###############################################################
#  Generated by:      Cadence Innovus 23.14-s088_1
#  OS:                Linux x86_64(Host ID mustatikli-be3.tuni.fi)
#  Generated on:      Mon Sep 22 14:50:03 2025
#  Design:            IN22FDX_S1DU_BFUG_W00256B032M04C128
#  Command:           write_lef_abstract -exclude_obs_layers $top_layer -stripe_pins -pg_pin_layers 10 [file join models [get_db flow_report_name] [get_db [current_design] .name].lef]
###############################################################

VERSION 5.8 ;

BUSBITCHARS "[]" ;
DIVIDERCHAR "/" ;

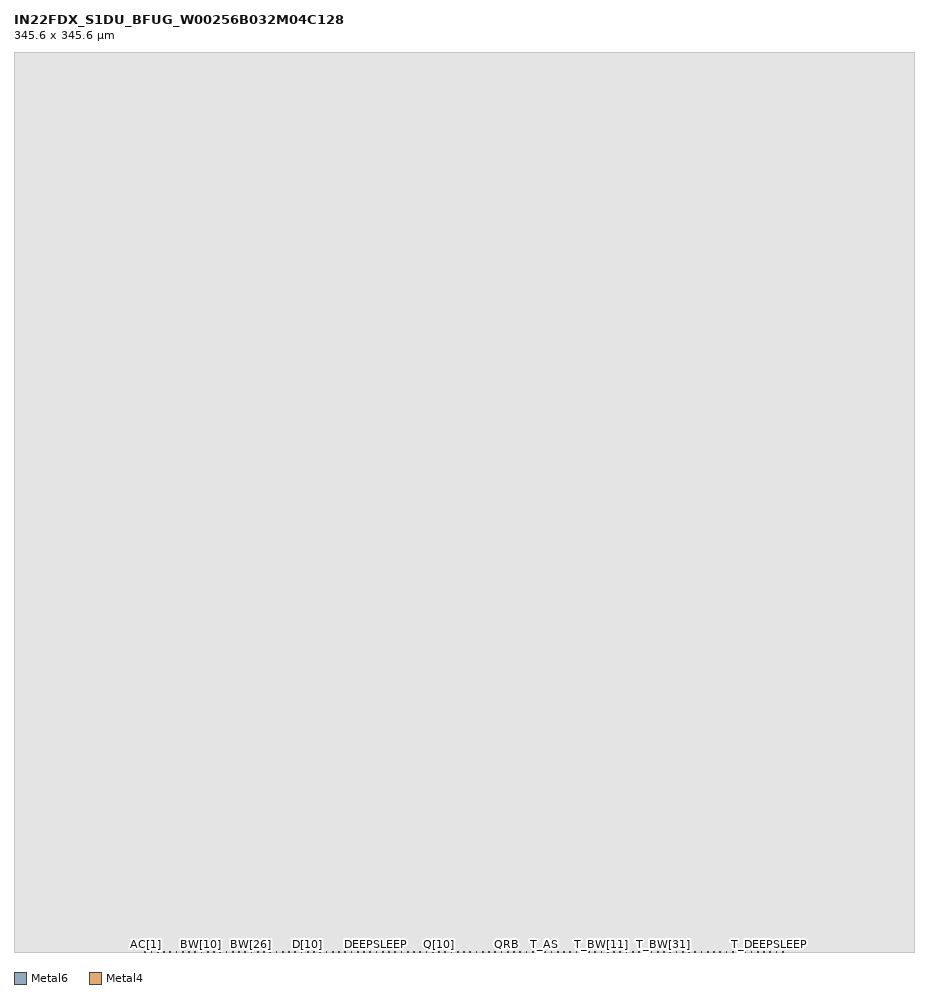
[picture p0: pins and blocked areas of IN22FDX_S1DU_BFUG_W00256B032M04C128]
MACRO IN22FDX_S1DU_BFUG_W00256B032M04C128
  CLASS BLOCK ;
  SIZE 345.600000 BY 345.600000 ;
  FOREIGN IN22FDX_S1DU_BFUG_W00256B032M04C128 0.000000 0.000000 ;
  ORIGIN 0 0 ;
  SYMMETRY X Y R90 ;
  PIN CLK
    DIRECTION INPUT ;
    USE SIGNAL ;
    PORT
      LAYER Metal6 ;
        RECT 98.460000 0.000000 98.540000 0.250000 ;
    END
  END CLK
  PIN CEN
    DIRECTION INPUT ;
    USE SIGNAL ;
    PORT
      LAYER Metal4 ;
        RECT 98.260000 0.000000 98.340000 0.250000 ;
    END
  END CEN
  PIN RDWEN
    DIRECTION INPUT ;
    USE SIGNAL ;
    PORT
      LAYER Metal6 ;
        RECT 199.260000 0.000000 199.340000 0.250000 ;
    END
  END RDWEN
  PIN DEEPSLEEP
    DIRECTION INPUT ;
    USE SIGNAL ;
    PORT
      LAYER Metal4 ;
        RECT 139.060000 0.000000 139.140000 0.250000 ;
    END
  END DEEPSLEEP
  PIN POWERGATE
    DIRECTION INPUT ;
    USE SIGNAL ;
    PORT
      LAYER Metal6 ;
        RECT 148.860000 0.000000 148.940000 0.250000 ;
    END
  END POWERGATE
  PIN AS
    DIRECTION INPUT ;
    USE SIGNAL ;
    PORT
      LAYER Metal4 ;
        RECT 52.660000 0.000000 52.740000 0.250000 ;
    END
  END AS
  PIN AW[4]
    DIRECTION INPUT ;
    USE SIGNAL ;
    PORT
      LAYER Metal6 ;
        RECT 57.660000 0.000000 57.740000 0.250000 ;
    END
  END AW[4]
  PIN AW[3]
    DIRECTION INPUT ;
    USE SIGNAL ;
    PORT
      LAYER Metal4 ;
        RECT 57.460000 0.000000 57.540000 0.250000 ;
    END
  END AW[3]
  PIN AW[2]
    DIRECTION INPUT ;
    USE SIGNAL ;
    PORT
      LAYER Metal6 ;
        RECT 55.260000 0.000000 55.340000 0.250000 ;
    END
  END AW[2]
  PIN AW[1]
    DIRECTION INPUT ;
    USE SIGNAL ;
    PORT
      LAYER Metal4 ;
        RECT 55.060000 0.000000 55.140000 0.250000 ;
    END
  END AW[1]
  PIN AW[0]
    DIRECTION INPUT ;
    USE SIGNAL ;
    PORT
      LAYER Metal6 ;
        RECT 52.860000 0.000000 52.940000 0.250000 ;
    END
  END AW[0]
  PIN AC[1]
    DIRECTION INPUT ;
    USE SIGNAL ;
    PORT
      LAYER Metal6 ;
        RECT 50.460000 0.000000 50.540000 0.250000 ;
    END
  END AC[1]
  PIN AC[0]
    DIRECTION INPUT ;
    USE SIGNAL ;
    PORT
      LAYER Metal4 ;
        RECT 50.260000 0.000000 50.340000 0.250000 ;
    END
  END AC[0]
  PIN D[31]
    DIRECTION INPUT ;
    USE SIGNAL ;
    PORT
      LAYER Metal6 ;
        RECT 136.860000 0.000000 136.940000 0.250000 ;
    END
  END D[31]
  PIN D[30]
    DIRECTION INPUT ;
    USE SIGNAL ;
    PORT
      LAYER Metal4 ;
        RECT 136.660000 0.000000 136.740000 0.250000 ;
    END
  END D[30]
  PIN D[29]
    DIRECTION INPUT ;
    USE SIGNAL ;
    PORT
      LAYER Metal6 ;
        RECT 134.460000 0.000000 134.540000 0.250000 ;
    END
  END D[29]
  PIN D[28]
    DIRECTION INPUT ;
    USE SIGNAL ;
    PORT
      LAYER Metal4 ;
        RECT 134.260000 0.000000 134.340000 0.250000 ;
    END
  END D[28]
  PIN D[27]
    DIRECTION INPUT ;
    USE SIGNAL ;
    PORT
      LAYER Metal6 ;
        RECT 132.060000 0.000000 132.140000 0.250000 ;
    END
  END D[27]
  PIN D[26]
    DIRECTION INPUT ;
    USE SIGNAL ;
    PORT
      LAYER Metal4 ;
        RECT 131.860000 0.000000 131.940000 0.250000 ;
    END
  END D[26]
  PIN D[25]
    DIRECTION INPUT ;
    USE SIGNAL ;
    PORT
      LAYER Metal6 ;
        RECT 129.660000 0.000000 129.740000 0.250000 ;
    END
  END D[25]
  PIN D[24]
    DIRECTION INPUT ;
    USE SIGNAL ;
    PORT
      LAYER Metal4 ;
        RECT 129.460000 0.000000 129.540000 0.250000 ;
    END
  END D[24]
  PIN D[23]
    DIRECTION INPUT ;
    USE SIGNAL ;
    PORT
      LAYER Metal6 ;
        RECT 127.260000 0.000000 127.340000 0.250000 ;
    END
  END D[23]
  PIN D[22]
    DIRECTION INPUT ;
    USE SIGNAL ;
    PORT
      LAYER Metal4 ;
        RECT 127.060000 0.000000 127.140000 0.250000 ;
    END
  END D[22]
  PIN D[21]
    DIRECTION INPUT ;
    USE SIGNAL ;
    PORT
      LAYER Metal6 ;
        RECT 124.860000 0.000000 124.940000 0.250000 ;
    END
  END D[21]
  PIN D[20]
    DIRECTION INPUT ;
    USE SIGNAL ;
    PORT
      LAYER Metal4 ;
        RECT 124.660000 0.000000 124.740000 0.250000 ;
    END
  END D[20]
  PIN D[19]
    DIRECTION INPUT ;
    USE SIGNAL ;
    PORT
      LAYER Metal6 ;
        RECT 122.460000 0.000000 122.540000 0.250000 ;
    END
  END D[19]
  PIN D[18]
    DIRECTION INPUT ;
    USE SIGNAL ;
    PORT
      LAYER Metal4 ;
        RECT 122.260000 0.000000 122.340000 0.250000 ;
    END
  END D[18]
  PIN D[17]
    DIRECTION INPUT ;
    USE SIGNAL ;
    PORT
      LAYER Metal6 ;
        RECT 120.060000 0.000000 120.140000 0.250000 ;
    END
  END D[17]
  PIN D[16]
    DIRECTION INPUT ;
    USE SIGNAL ;
    PORT
      LAYER Metal4 ;
        RECT 119.860000 0.000000 119.940000 0.250000 ;
    END
  END D[16]
  PIN D[15]
    DIRECTION INPUT ;
    USE SIGNAL ;
    PORT
      LAYER Metal6 ;
        RECT 117.660000 0.000000 117.740000 0.250000 ;
    END
  END D[15]
  PIN D[14]
    DIRECTION INPUT ;
    USE SIGNAL ;
    PORT
      LAYER Metal4 ;
        RECT 117.460000 0.000000 117.540000 0.250000 ;
    END
  END D[14]
  PIN D[13]
    DIRECTION INPUT ;
    USE SIGNAL ;
    PORT
      LAYER Metal6 ;
        RECT 115.260000 0.000000 115.340000 0.250000 ;
    END
  END D[13]
  PIN D[12]
    DIRECTION INPUT ;
    USE SIGNAL ;
    PORT
      LAYER Metal4 ;
        RECT 115.060000 0.000000 115.140000 0.250000 ;
    END
  END D[12]
  PIN D[11]
    DIRECTION INPUT ;
    USE SIGNAL ;
    PORT
      LAYER Metal6 ;
        RECT 112.860000 0.000000 112.940000 0.250000 ;
    END
  END D[11]
  PIN D[10]
    DIRECTION INPUT ;
    USE SIGNAL ;
    PORT
      LAYER Metal4 ;
        RECT 112.660000 0.000000 112.740000 0.250000 ;
    END
  END D[10]
  PIN D[9]
    DIRECTION INPUT ;
    USE SIGNAL ;
    PORT
      LAYER Metal6 ;
        RECT 110.460000 0.000000 110.540000 0.250000 ;
    END
  END D[9]
  PIN D[8]
    DIRECTION INPUT ;
    USE SIGNAL ;
    PORT
      LAYER Metal4 ;
        RECT 110.260000 0.000000 110.340000 0.250000 ;
    END
  END D[8]
  PIN D[7]
    DIRECTION INPUT ;
    USE SIGNAL ;
    PORT
      LAYER Metal6 ;
        RECT 108.060000 0.000000 108.140000 0.250000 ;
    END
  END D[7]
  PIN D[6]
    DIRECTION INPUT ;
    USE SIGNAL ;
    PORT
      LAYER Metal4 ;
        RECT 107.860000 0.000000 107.940000 0.250000 ;
    END
  END D[6]
  PIN D[5]
    DIRECTION INPUT ;
    USE SIGNAL ;
    PORT
      LAYER Metal6 ;
        RECT 105.660000 0.000000 105.740000 0.250000 ;
    END
  END D[5]
  PIN D[4]
    DIRECTION INPUT ;
    USE SIGNAL ;
    PORT
      LAYER Metal4 ;
        RECT 105.460000 0.000000 105.540000 0.250000 ;
    END
  END D[4]
  PIN D[3]
    DIRECTION INPUT ;
    USE SIGNAL ;
    PORT
      LAYER Metal6 ;
        RECT 103.260000 0.000000 103.340000 0.250000 ;
    END
  END D[3]
  PIN D[2]
    DIRECTION INPUT ;
    USE SIGNAL ;
    PORT
      LAYER Metal4 ;
        RECT 103.060000 0.000000 103.140000 0.250000 ;
    END
  END D[2]
  PIN D[1]
    DIRECTION INPUT ;
    USE SIGNAL ;
    PORT
      LAYER Metal6 ;
        RECT 100.860000 0.000000 100.940000 0.250000 ;
    END
  END D[1]
  PIN D[0]
    DIRECTION INPUT ;
    USE SIGNAL ;
    PORT
      LAYER Metal4 ;
        RECT 100.660000 0.000000 100.740000 0.250000 ;
    END
  END D[0]
  PIN BW[31]
    DIRECTION INPUT ;
    USE SIGNAL ;
    PORT
      LAYER Metal6 ;
        RECT 96.060000 0.000000 96.140000 0.250000 ;
    END
  END BW[31]
  PIN BW[30]
    DIRECTION INPUT ;
    USE SIGNAL ;
    PORT
      LAYER Metal4 ;
        RECT 95.860000 0.000000 95.940000 0.250000 ;
    END
  END BW[30]
  PIN BW[29]
    DIRECTION INPUT ;
    USE SIGNAL ;
    PORT
      LAYER Metal6 ;
        RECT 93.660000 0.000000 93.740000 0.250000 ;
    END
  END BW[29]
  PIN BW[28]
    DIRECTION INPUT ;
    USE SIGNAL ;
    PORT
      LAYER Metal4 ;
        RECT 93.460000 0.000000 93.540000 0.250000 ;
    END
  END BW[28]
  PIN BW[27]
    DIRECTION INPUT ;
    USE SIGNAL ;
    PORT
      LAYER Metal6 ;
        RECT 91.260000 0.000000 91.340000 0.250000 ;
    END
  END BW[27]
  PIN BW[26]
    DIRECTION INPUT ;
    USE SIGNAL ;
    PORT
      LAYER Metal4 ;
        RECT 91.060000 0.000000 91.140000 0.250000 ;
    END
  END BW[26]
  PIN BW[25]
    DIRECTION INPUT ;
    USE SIGNAL ;
    PORT
      LAYER Metal6 ;
        RECT 88.860000 0.000000 88.940000 0.250000 ;
    END
  END BW[25]
  PIN BW[24]
    DIRECTION INPUT ;
    USE SIGNAL ;
    PORT
      LAYER Metal4 ;
        RECT 88.660000 0.000000 88.740000 0.250000 ;
    END
  END BW[24]
  PIN BW[23]
    DIRECTION INPUT ;
    USE SIGNAL ;
    PORT
      LAYER Metal6 ;
        RECT 86.460000 0.000000 86.540000 0.250000 ;
    END
  END BW[23]
  PIN BW[22]
    DIRECTION INPUT ;
    USE SIGNAL ;
    PORT
      LAYER Metal4 ;
        RECT 86.260000 0.000000 86.340000 0.250000 ;
    END
  END BW[22]
  PIN BW[21]
    DIRECTION INPUT ;
    USE SIGNAL ;
    PORT
      LAYER Metal6 ;
        RECT 84.060000 0.000000 84.140000 0.250000 ;
    END
  END BW[21]
  PIN BW[20]
    DIRECTION INPUT ;
    USE SIGNAL ;
    PORT
      LAYER Metal4 ;
        RECT 83.860000 0.000000 83.940000 0.250000 ;
    END
  END BW[20]
  PIN BW[19]
    DIRECTION INPUT ;
    USE SIGNAL ;
    PORT
      LAYER Metal6 ;
        RECT 81.660000 0.000000 81.740000 0.250000 ;
    END
  END BW[19]
  PIN BW[18]
    DIRECTION INPUT ;
    USE SIGNAL ;
    PORT
      LAYER Metal4 ;
        RECT 81.460000 0.000000 81.540000 0.250000 ;
    END
  END BW[18]
  PIN BW[17]
    DIRECTION INPUT ;
    USE SIGNAL ;
    PORT
      LAYER Metal6 ;
        RECT 79.260000 0.000000 79.340000 0.250000 ;
    END
  END BW[17]
  PIN BW[16]
    DIRECTION INPUT ;
    USE SIGNAL ;
    PORT
      LAYER Metal4 ;
        RECT 79.060000 0.000000 79.140000 0.250000 ;
    END
  END BW[16]
  PIN BW[15]
    DIRECTION INPUT ;
    USE SIGNAL ;
    PORT
      LAYER Metal6 ;
        RECT 76.860000 0.000000 76.940000 0.250000 ;
    END
  END BW[15]
  PIN BW[14]
    DIRECTION INPUT ;
    USE SIGNAL ;
    PORT
      LAYER Metal4 ;
        RECT 76.660000 0.000000 76.740000 0.250000 ;
    END
  END BW[14]
  PIN BW[13]
    DIRECTION INPUT ;
    USE SIGNAL ;
    PORT
      LAYER Metal6 ;
        RECT 74.460000 0.000000 74.540000 0.250000 ;
    END
  END BW[13]
  PIN BW[12]
    DIRECTION INPUT ;
    USE SIGNAL ;
    PORT
      LAYER Metal4 ;
        RECT 74.260000 0.000000 74.340000 0.250000 ;
    END
  END BW[12]
  PIN BW[11]
    DIRECTION INPUT ;
    USE SIGNAL ;
    PORT
      LAYER Metal6 ;
        RECT 72.060000 0.000000 72.140000 0.250000 ;
    END
  END BW[11]
  PIN BW[10]
    DIRECTION INPUT ;
    USE SIGNAL ;
    PORT
      LAYER Metal4 ;
        RECT 71.860000 0.000000 71.940000 0.250000 ;
    END
  END BW[10]
  PIN BW[9]
    DIRECTION INPUT ;
    USE SIGNAL ;
    PORT
      LAYER Metal6 ;
        RECT 69.660000 0.000000 69.740000 0.250000 ;
    END
  END BW[9]
  PIN BW[8]
    DIRECTION INPUT ;
    USE SIGNAL ;
    PORT
      LAYER Metal4 ;
        RECT 69.460000 0.000000 69.540000 0.250000 ;
    END
  END BW[8]
  PIN BW[7]
    DIRECTION INPUT ;
    USE SIGNAL ;
    PORT
      LAYER Metal6 ;
        RECT 67.260000 0.000000 67.340000 0.250000 ;
    END
  END BW[7]
  PIN BW[6]
    DIRECTION INPUT ;
    USE SIGNAL ;
    PORT
      LAYER Metal4 ;
        RECT 67.060000 0.000000 67.140000 0.250000 ;
    END
  END BW[6]
  PIN BW[5]
    DIRECTION INPUT ;
    USE SIGNAL ;
    PORT
      LAYER Metal6 ;
        RECT 64.860000 0.000000 64.940000 0.250000 ;
    END
  END BW[5]
  PIN BW[4]
    DIRECTION INPUT ;
    USE SIGNAL ;
    PORT
      LAYER Metal4 ;
        RECT 64.660000 0.000000 64.740000 0.250000 ;
    END
  END BW[4]
  PIN BW[3]
    DIRECTION INPUT ;
    USE SIGNAL ;
    PORT
      LAYER Metal6 ;
        RECT 62.460000 0.000000 62.540000 0.250000 ;
    END
  END BW[3]
  PIN BW[2]
    DIRECTION INPUT ;
    USE SIGNAL ;
    PORT
      LAYER Metal4 ;
        RECT 62.260000 0.000000 62.340000 0.250000 ;
    END
  END BW[2]
  PIN BW[1]
    DIRECTION INPUT ;
    USE SIGNAL ;
    PORT
      LAYER Metal6 ;
        RECT 60.060000 0.000000 60.140000 0.250000 ;
    END
  END BW[1]
  PIN BW[0]
    DIRECTION INPUT ;
    USE SIGNAL ;
    PORT
      LAYER Metal4 ;
        RECT 59.860000 0.000000 59.940000 0.250000 ;
    END
  END BW[0]
  PIN T_BIST
    DIRECTION INPUT ;
    USE SIGNAL ;
    PORT
      LAYER Metal4 ;
        RECT 211.060000 0.000000 211.140000 0.250000 ;
    END
  END T_BIST
  PIN T_LOGIC
    DIRECTION INPUT ;
    USE SIGNAL ;
    PORT
      LAYER Metal6 ;
        RECT 290.460000 0.000000 290.540000 0.250000 ;
    END
  END T_LOGIC
  PIN T_CEN
    DIRECTION INPUT ;
    USE SIGNAL ;
    PORT
      LAYER Metal6 ;
        RECT 249.660000 0.000000 249.740000 0.250000 ;
    END
  END T_CEN
  PIN T_RDWEN
    DIRECTION INPUT ;
    USE SIGNAL ;
    PORT
      LAYER Metal6 ;
        RECT 292.860000 0.000000 292.940000 0.250000 ;
    END
  END T_RDWEN
  PIN T_DEEPSLEEP
    DIRECTION INPUT ;
    USE SIGNAL ;
    PORT
      LAYER Metal4 ;
        RECT 290.260000 0.000000 290.340000 0.250000 ;
    END
  END T_DEEPSLEEP
  PIN T_POWERGATE
    DIRECTION INPUT ;
    USE SIGNAL ;
    PORT
      LAYER Metal4 ;
        RECT 292.660000 0.000000 292.740000 0.250000 ;
    END
  END T_POWERGATE
  PIN T_AS
    DIRECTION INPUT ;
    USE SIGNAL ;
    PORT
      LAYER Metal4 ;
        RECT 203.860000 0.000000 203.940000 0.250000 ;
    END
  END T_AS
  PIN T_AW[4]
    DIRECTION INPUT ;
    USE SIGNAL ;
    PORT
      LAYER Metal6 ;
        RECT 208.860000 0.000000 208.940000 0.250000 ;
    END
  END T_AW[4]
  PIN T_AW[3]
    DIRECTION INPUT ;
    USE SIGNAL ;
    PORT
      LAYER Metal4 ;
        RECT 208.660000 0.000000 208.740000 0.250000 ;
    END
  END T_AW[3]
  PIN T_AW[2]
    DIRECTION INPUT ;
    USE SIGNAL ;
    PORT
      LAYER Metal6 ;
        RECT 206.460000 0.000000 206.540000 0.250000 ;
    END
  END T_AW[2]
  PIN T_AW[1]
    DIRECTION INPUT ;
    USE SIGNAL ;
    PORT
      LAYER Metal4 ;
        RECT 206.260000 0.000000 206.340000 0.250000 ;
    END
  END T_AW[1]
  PIN T_AW[0]
    DIRECTION INPUT ;
    USE SIGNAL ;
    PORT
      LAYER Metal6 ;
        RECT 204.060000 0.000000 204.140000 0.250000 ;
    END
  END T_AW[0]
  PIN T_AC[1]
    DIRECTION INPUT ;
    USE SIGNAL ;
    PORT
      LAYER Metal6 ;
        RECT 201.660000 0.000000 201.740000 0.250000 ;
    END
  END T_AC[1]
  PIN T_AC[0]
    DIRECTION INPUT ;
    USE SIGNAL ;
    PORT
      LAYER Metal4 ;
        RECT 201.460000 0.000000 201.540000 0.250000 ;
    END
  END T_AC[0]
  PIN T_D[31]
    DIRECTION INPUT ;
    USE SIGNAL ;
    PORT
      LAYER Metal6 ;
        RECT 288.060000 0.000000 288.140000 0.250000 ;
    END
  END T_D[31]
  PIN T_D[30]
    DIRECTION INPUT ;
    USE SIGNAL ;
    PORT
      LAYER Metal4 ;
        RECT 287.860000 0.000000 287.940000 0.250000 ;
    END
  END T_D[30]
  PIN T_D[29]
    DIRECTION INPUT ;
    USE SIGNAL ;
    PORT
      LAYER Metal6 ;
        RECT 285.660000 0.000000 285.740000 0.250000 ;
    END
  END T_D[29]
  PIN T_D[28]
    DIRECTION INPUT ;
    USE SIGNAL ;
    PORT
      LAYER Metal4 ;
        RECT 285.460000 0.000000 285.540000 0.250000 ;
    END
  END T_D[28]
  PIN T_D[27]
    DIRECTION INPUT ;
    USE SIGNAL ;
    PORT
      LAYER Metal6 ;
        RECT 283.260000 0.000000 283.340000 0.250000 ;
    END
  END T_D[27]
  PIN T_D[26]
    DIRECTION INPUT ;
    USE SIGNAL ;
    PORT
      LAYER Metal4 ;
        RECT 283.060000 0.000000 283.140000 0.250000 ;
    END
  END T_D[26]
  PIN T_D[25]
    DIRECTION INPUT ;
    USE SIGNAL ;
    PORT
      LAYER Metal6 ;
        RECT 280.860000 0.000000 280.940000 0.250000 ;
    END
  END T_D[25]
  PIN T_D[24]
    DIRECTION INPUT ;
    USE SIGNAL ;
    PORT
      LAYER Metal4 ;
        RECT 280.660000 0.000000 280.740000 0.250000 ;
    END
  END T_D[24]
  PIN T_D[23]
    DIRECTION INPUT ;
    USE SIGNAL ;
    PORT
      LAYER Metal6 ;
        RECT 278.460000 0.000000 278.540000 0.250000 ;
    END
  END T_D[23]
  PIN T_D[22]
    DIRECTION INPUT ;
    USE SIGNAL ;
    PORT
      LAYER Metal4 ;
        RECT 278.260000 0.000000 278.340000 0.250000 ;
    END
  END T_D[22]
  PIN T_D[21]
    DIRECTION INPUT ;
    USE SIGNAL ;
    PORT
      LAYER Metal6 ;
        RECT 276.060000 0.000000 276.140000 0.250000 ;
    END
  END T_D[21]
  PIN T_D[20]
    DIRECTION INPUT ;
    USE SIGNAL ;
    PORT
      LAYER Metal4 ;
        RECT 275.860000 0.000000 275.940000 0.250000 ;
    END
  END T_D[20]
  PIN T_D[19]
    DIRECTION INPUT ;
    USE SIGNAL ;
    PORT
      LAYER Metal6 ;
        RECT 273.660000 0.000000 273.740000 0.250000 ;
    END
  END T_D[19]
  PIN T_D[18]
    DIRECTION INPUT ;
    USE SIGNAL ;
    PORT
      LAYER Metal4 ;
        RECT 273.460000 0.000000 273.540000 0.250000 ;
    END
  END T_D[18]
  PIN T_D[17]
    DIRECTION INPUT ;
    USE SIGNAL ;
    PORT
      LAYER Metal6 ;
        RECT 271.260000 0.000000 271.340000 0.250000 ;
    END
  END T_D[17]
  PIN T_D[16]
    DIRECTION INPUT ;
    USE SIGNAL ;
    PORT
      LAYER Metal4 ;
        RECT 271.060000 0.000000 271.140000 0.250000 ;
    END
  END T_D[16]
  PIN T_D[15]
    DIRECTION INPUT ;
    USE SIGNAL ;
    PORT
      LAYER Metal6 ;
        RECT 268.860000 0.000000 268.940000 0.250000 ;
    END
  END T_D[15]
  PIN T_D[14]
    DIRECTION INPUT ;
    USE SIGNAL ;
    PORT
      LAYER Metal4 ;
        RECT 268.660000 0.000000 268.740000 0.250000 ;
    END
  END T_D[14]
  PIN T_D[13]
    DIRECTION INPUT ;
    USE SIGNAL ;
    PORT
      LAYER Metal6 ;
        RECT 266.460000 0.000000 266.540000 0.250000 ;
    END
  END T_D[13]
  PIN T_D[12]
    DIRECTION INPUT ;
    USE SIGNAL ;
    PORT
      LAYER Metal4 ;
        RECT 266.260000 0.000000 266.340000 0.250000 ;
    END
  END T_D[12]
  PIN T_D[11]
    DIRECTION INPUT ;
    USE SIGNAL ;
    PORT
      LAYER Metal6 ;
        RECT 264.060000 0.000000 264.140000 0.250000 ;
    END
  END T_D[11]
  PIN T_D[10]
    DIRECTION INPUT ;
    USE SIGNAL ;
    PORT
      LAYER Metal4 ;
        RECT 263.860000 0.000000 263.940000 0.250000 ;
    END
  END T_D[10]
  PIN T_D[9]
    DIRECTION INPUT ;
    USE SIGNAL ;
    PORT
      LAYER Metal6 ;
        RECT 261.660000 0.000000 261.740000 0.250000 ;
    END
  END T_D[9]
  PIN T_D[8]
    DIRECTION INPUT ;
    USE SIGNAL ;
    PORT
      LAYER Metal4 ;
        RECT 261.460000 0.000000 261.540000 0.250000 ;
    END
  END T_D[8]
  PIN T_D[7]
    DIRECTION INPUT ;
    USE SIGNAL ;
    PORT
      LAYER Metal6 ;
        RECT 259.260000 0.000000 259.340000 0.250000 ;
    END
  END T_D[7]
  PIN T_D[6]
    DIRECTION INPUT ;
    USE SIGNAL ;
    PORT
      LAYER Metal4 ;
        RECT 259.060000 0.000000 259.140000 0.250000 ;
    END
  END T_D[6]
  PIN T_D[5]
    DIRECTION INPUT ;
    USE SIGNAL ;
    PORT
      LAYER Metal6 ;
        RECT 256.860000 0.000000 256.940000 0.250000 ;
    END
  END T_D[5]
  PIN T_D[4]
    DIRECTION INPUT ;
    USE SIGNAL ;
    PORT
      LAYER Metal4 ;
        RECT 256.660000 0.000000 256.740000 0.250000 ;
    END
  END T_D[4]
  PIN T_D[3]
    DIRECTION INPUT ;
    USE SIGNAL ;
    PORT
      LAYER Metal6 ;
        RECT 254.460000 0.000000 254.540000 0.250000 ;
    END
  END T_D[3]
  PIN T_D[2]
    DIRECTION INPUT ;
    USE SIGNAL ;
    PORT
      LAYER Metal4 ;
        RECT 254.260000 0.000000 254.340000 0.250000 ;
    END
  END T_D[2]
  PIN T_D[1]
    DIRECTION INPUT ;
    USE SIGNAL ;
    PORT
      LAYER Metal6 ;
        RECT 252.060000 0.000000 252.140000 0.250000 ;
    END
  END T_D[1]
  PIN T_D[0]
    DIRECTION INPUT ;
    USE SIGNAL ;
    PORT
      LAYER Metal4 ;
        RECT 251.860000 0.000000 251.940000 0.250000 ;
    END
  END T_D[0]
  PIN T_BW[31]
    DIRECTION INPUT ;
    USE SIGNAL ;
    PORT
      LAYER Metal4 ;
        RECT 249.460000 0.000000 249.540000 0.250000 ;
    END
  END T_BW[31]
  PIN T_BW[30]
    DIRECTION INPUT ;
    USE SIGNAL ;
    PORT
      LAYER Metal6 ;
        RECT 247.260000 0.000000 247.340000 0.250000 ;
    END
  END T_BW[30]
  PIN T_BW[29]
    DIRECTION INPUT ;
    USE SIGNAL ;
    PORT
      LAYER Metal4 ;
        RECT 247.060000 0.000000 247.140000 0.250000 ;
    END
  END T_BW[29]
  PIN T_BW[28]
    DIRECTION INPUT ;
    USE SIGNAL ;
    PORT
      LAYER Metal6 ;
        RECT 244.860000 0.000000 244.940000 0.250000 ;
    END
  END T_BW[28]
  PIN T_BW[27]
    DIRECTION INPUT ;
    USE SIGNAL ;
    PORT
      LAYER Metal4 ;
        RECT 244.660000 0.000000 244.740000 0.250000 ;
    END
  END T_BW[27]
  PIN T_BW[26]
    DIRECTION INPUT ;
    USE SIGNAL ;
    PORT
      LAYER Metal6 ;
        RECT 242.460000 0.000000 242.540000 0.250000 ;
    END
  END T_BW[26]
  PIN T_BW[25]
    DIRECTION INPUT ;
    USE SIGNAL ;
    PORT
      LAYER Metal4 ;
        RECT 242.260000 0.000000 242.340000 0.250000 ;
    END
  END T_BW[25]
  PIN T_BW[24]
    DIRECTION INPUT ;
    USE SIGNAL ;
    PORT
      LAYER Metal6 ;
        RECT 240.060000 0.000000 240.140000 0.250000 ;
    END
  END T_BW[24]
  PIN T_BW[23]
    DIRECTION INPUT ;
    USE SIGNAL ;
    PORT
      LAYER Metal4 ;
        RECT 239.860000 0.000000 239.940000 0.250000 ;
    END
  END T_BW[23]
  PIN T_BW[22]
    DIRECTION INPUT ;
    USE SIGNAL ;
    PORT
      LAYER Metal6 ;
        RECT 237.660000 0.000000 237.740000 0.250000 ;
    END
  END T_BW[22]
  PIN T_BW[21]
    DIRECTION INPUT ;
    USE SIGNAL ;
    PORT
      LAYER Metal4 ;
        RECT 237.460000 0.000000 237.540000 0.250000 ;
    END
  END T_BW[21]
  PIN T_BW[20]
    DIRECTION INPUT ;
    USE SIGNAL ;
    PORT
      LAYER Metal6 ;
        RECT 235.260000 0.000000 235.340000 0.250000 ;
    END
  END T_BW[20]
  PIN T_BW[19]
    DIRECTION INPUT ;
    USE SIGNAL ;
    PORT
      LAYER Metal4 ;
        RECT 235.060000 0.000000 235.140000 0.250000 ;
    END
  END T_BW[19]
  PIN T_BW[18]
    DIRECTION INPUT ;
    USE SIGNAL ;
    PORT
      LAYER Metal6 ;
        RECT 232.860000 0.000000 232.940000 0.250000 ;
    END
  END T_BW[18]
  PIN T_BW[17]
    DIRECTION INPUT ;
    USE SIGNAL ;
    PORT
      LAYER Metal4 ;
        RECT 232.660000 0.000000 232.740000 0.250000 ;
    END
  END T_BW[17]
  PIN T_BW[16]
    DIRECTION INPUT ;
    USE SIGNAL ;
    PORT
      LAYER Metal6 ;
        RECT 230.460000 0.000000 230.540000 0.250000 ;
    END
  END T_BW[16]
  PIN T_BW[15]
    DIRECTION INPUT ;
    USE SIGNAL ;
    PORT
      LAYER Metal4 ;
        RECT 230.260000 0.000000 230.340000 0.250000 ;
    END
  END T_BW[15]
  PIN T_BW[14]
    DIRECTION INPUT ;
    USE SIGNAL ;
    PORT
      LAYER Metal6 ;
        RECT 228.060000 0.000000 228.140000 0.250000 ;
    END
  END T_BW[14]
  PIN T_BW[13]
    DIRECTION INPUT ;
    USE SIGNAL ;
    PORT
      LAYER Metal4 ;
        RECT 227.860000 0.000000 227.940000 0.250000 ;
    END
  END T_BW[13]
  PIN T_BW[12]
    DIRECTION INPUT ;
    USE SIGNAL ;
    PORT
      LAYER Metal6 ;
        RECT 225.660000 0.000000 225.740000 0.250000 ;
    END
  END T_BW[12]
  PIN T_BW[11]
    DIRECTION INPUT ;
    USE SIGNAL ;
    PORT
      LAYER Metal4 ;
        RECT 225.460000 0.000000 225.540000 0.250000 ;
    END
  END T_BW[11]
  PIN T_BW[10]
    DIRECTION INPUT ;
    USE SIGNAL ;
    PORT
      LAYER Metal6 ;
        RECT 223.260000 0.000000 223.340000 0.250000 ;
    END
  END T_BW[10]
  PIN T_BW[9]
    DIRECTION INPUT ;
    USE SIGNAL ;
    PORT
      LAYER Metal4 ;
        RECT 223.060000 0.000000 223.140000 0.250000 ;
    END
  END T_BW[9]
  PIN T_BW[8]
    DIRECTION INPUT ;
    USE SIGNAL ;
    PORT
      LAYER Metal6 ;
        RECT 220.860000 0.000000 220.940000 0.250000 ;
    END
  END T_BW[8]
  PIN T_BW[7]
    DIRECTION INPUT ;
    USE SIGNAL ;
    PORT
      LAYER Metal4 ;
        RECT 220.660000 0.000000 220.740000 0.250000 ;
    END
  END T_BW[7]
  PIN T_BW[6]
    DIRECTION INPUT ;
    USE SIGNAL ;
    PORT
      LAYER Metal6 ;
        RECT 218.460000 0.000000 218.540000 0.250000 ;
    END
  END T_BW[6]
  PIN T_BW[5]
    DIRECTION INPUT ;
    USE SIGNAL ;
    PORT
      LAYER Metal4 ;
        RECT 218.260000 0.000000 218.340000 0.250000 ;
    END
  END T_BW[5]
  PIN T_BW[4]
    DIRECTION INPUT ;
    USE SIGNAL ;
    PORT
      LAYER Metal6 ;
        RECT 216.060000 0.000000 216.140000 0.250000 ;
    END
  END T_BW[4]
  PIN T_BW[3]
    DIRECTION INPUT ;
    USE SIGNAL ;
    PORT
      LAYER Metal4 ;
        RECT 215.860000 0.000000 215.940000 0.250000 ;
    END
  END T_BW[3]
  PIN T_BW[2]
    DIRECTION INPUT ;
    USE SIGNAL ;
    PORT
      LAYER Metal6 ;
        RECT 213.660000 0.000000 213.740000 0.250000 ;
    END
  END T_BW[2]
  PIN T_BW[1]
    DIRECTION INPUT ;
    USE SIGNAL ;
    PORT
      LAYER Metal4 ;
        RECT 213.460000 0.000000 213.540000 0.250000 ;
    END
  END T_BW[1]
  PIN T_BW[0]
    DIRECTION INPUT ;
    USE SIGNAL ;
    PORT
      LAYER Metal6 ;
        RECT 211.260000 0.000000 211.340000 0.250000 ;
    END
  END T_BW[0]
  PIN T_WBT
    DIRECTION INPUT ;
    USE SIGNAL ;
    PORT
      LAYER Metal6 ;
        RECT 295.260000 0.000000 295.340000 0.250000 ;
    END
  END T_WBT
  PIN T_STAB
    DIRECTION INPUT ;
    USE SIGNAL ;
    PORT
      LAYER Metal4 ;
        RECT 295.060000 0.000000 295.140000 0.250000 ;
    END
  END T_STAB
  PIN MA_SAWL[1]
    DIRECTION INPUT ;
    USE SIGNAL ;
    PORT
      LAYER Metal4 ;
        RECT 141.460000 0.000000 141.540000 0.250000 ;
    END
  END MA_SAWL[1]
  PIN MA_SAWL[0]
    DIRECTION INPUT ;
    USE SIGNAL ;
    PORT
      LAYER Metal6 ;
        RECT 139.260000 0.000000 139.340000 0.250000 ;
    END
  END MA_SAWL[0]
  PIN MA_WL[1]
    DIRECTION INPUT ;
    USE SIGNAL ;
    PORT
      LAYER Metal4 ;
        RECT 143.860000 0.000000 143.940000 0.250000 ;
    END
  END MA_WL[1]
  PIN MA_WL[0]
    DIRECTION INPUT ;
    USE SIGNAL ;
    PORT
      LAYER Metal6 ;
        RECT 141.660000 0.000000 141.740000 0.250000 ;
    END
  END MA_WL[0]
  PIN MA_WRAS[1]
    DIRECTION INPUT ;
    USE SIGNAL ;
    PORT
      LAYER Metal4 ;
        RECT 146.260000 0.000000 146.340000 0.250000 ;
    END
  END MA_WRAS[1]
  PIN MA_WRAS[0]
    DIRECTION INPUT ;
    USE SIGNAL ;
    PORT
      LAYER Metal6 ;
        RECT 144.060000 0.000000 144.140000 0.250000 ;
    END
  END MA_WRAS[0]
  PIN MA_WRASD
    DIRECTION INPUT ;
    USE SIGNAL ;
    PORT
      LAYER Metal6 ;
        RECT 146.460000 0.000000 146.540000 0.250000 ;
    END
  END MA_WRASD
  PIN RBE
    DIRECTION INPUT ;
    USE SIGNAL ;
    PORT
      LAYER Metal6 ;
        RECT 189.660000 0.000000 189.740000 0.250000 ;
    END
  END RBE
  PIN RBF0A[6]
    DIRECTION INPUT ;
    USE SIGNAL ;
    PORT
      LAYER Metal4 ;
        RECT 199.060000 0.000000 199.140000 0.250000 ;
    END
  END RBF0A[6]
  PIN RBF0A[5]
    DIRECTION INPUT ;
    USE SIGNAL ;
    PORT
      LAYER Metal6 ;
        RECT 196.860000 0.000000 196.940000 0.250000 ;
    END
  END RBF0A[5]
  PIN RBF0A[4]
    DIRECTION INPUT ;
    USE SIGNAL ;
    PORT
      LAYER Metal4 ;
        RECT 196.660000 0.000000 196.740000 0.250000 ;
    END
  END RBF0A[4]
  PIN RBF0A[3]
    DIRECTION INPUT ;
    USE SIGNAL ;
    PORT
      LAYER Metal6 ;
        RECT 194.460000 0.000000 194.540000 0.250000 ;
    END
  END RBF0A[3]
  PIN RBF0A[2]
    DIRECTION INPUT ;
    USE SIGNAL ;
    PORT
      LAYER Metal4 ;
        RECT 194.260000 0.000000 194.340000 0.250000 ;
    END
  END RBF0A[2]
  PIN RBF0A[1]
    DIRECTION INPUT ;
    USE SIGNAL ;
    PORT
      LAYER Metal6 ;
        RECT 192.060000 0.000000 192.140000 0.250000 ;
    END
  END RBF0A[1]
  PIN RBF0A[0]
    DIRECTION INPUT ;
    USE SIGNAL ;
    PORT
      LAYER Metal4 ;
        RECT 191.860000 0.000000 191.940000 0.250000 ;
    END
  END RBF0A[0]
  PIN QRB
    DIRECTION OUTPUT ;
    USE SIGNAL ;
    PORT
      LAYER Metal4 ;
        RECT 189.460000 0.000000 189.540000 0.250000 ;
    END
  END QRB
  PIN Q[31]
    DIRECTION OUTPUT ;
    USE SIGNAL ;
    PORT
      LAYER Metal6 ;
        RECT 187.260000 0.000000 187.340000 0.250000 ;
    END
  END Q[31]
  PIN Q[30]
    DIRECTION OUTPUT ;
    USE SIGNAL ;
    PORT
      LAYER Metal4 ;
        RECT 187.060000 0.000000 187.140000 0.250000 ;
    END
  END Q[30]
  PIN Q[29]
    DIRECTION OUTPUT ;
    USE SIGNAL ;
    PORT
      LAYER Metal6 ;
        RECT 184.860000 0.000000 184.940000 0.250000 ;
    END
  END Q[29]
  PIN Q[28]
    DIRECTION OUTPUT ;
    USE SIGNAL ;
    PORT
      LAYER Metal4 ;
        RECT 184.660000 0.000000 184.740000 0.250000 ;
    END
  END Q[28]
  PIN Q[27]
    DIRECTION OUTPUT ;
    USE SIGNAL ;
    PORT
      LAYER Metal6 ;
        RECT 182.460000 0.000000 182.540000 0.250000 ;
    END
  END Q[27]
  PIN Q[26]
    DIRECTION OUTPUT ;
    USE SIGNAL ;
    PORT
      LAYER Metal4 ;
        RECT 182.260000 0.000000 182.340000 0.250000 ;
    END
  END Q[26]
  PIN Q[25]
    DIRECTION OUTPUT ;
    USE SIGNAL ;
    PORT
      LAYER Metal6 ;
        RECT 180.060000 0.000000 180.140000 0.250000 ;
    END
  END Q[25]
  PIN Q[24]
    DIRECTION OUTPUT ;
    USE SIGNAL ;
    PORT
      LAYER Metal4 ;
        RECT 179.860000 0.000000 179.940000 0.250000 ;
    END
  END Q[24]
  PIN Q[23]
    DIRECTION OUTPUT ;
    USE SIGNAL ;
    PORT
      LAYER Metal6 ;
        RECT 177.660000 0.000000 177.740000 0.250000 ;
    END
  END Q[23]
  PIN Q[22]
    DIRECTION OUTPUT ;
    USE SIGNAL ;
    PORT
      LAYER Metal4 ;
        RECT 177.460000 0.000000 177.540000 0.250000 ;
    END
  END Q[22]
  PIN Q[21]
    DIRECTION OUTPUT ;
    USE SIGNAL ;
    PORT
      LAYER Metal6 ;
        RECT 175.260000 0.000000 175.340000 0.250000 ;
    END
  END Q[21]
  PIN Q[20]
    DIRECTION OUTPUT ;
    USE SIGNAL ;
    PORT
      LAYER Metal4 ;
        RECT 175.060000 0.000000 175.140000 0.250000 ;
    END
  END Q[20]
  PIN Q[19]
    DIRECTION OUTPUT ;
    USE SIGNAL ;
    PORT
      LAYER Metal6 ;
        RECT 172.860000 0.000000 172.940000 0.250000 ;
    END
  END Q[19]
  PIN Q[18]
    DIRECTION OUTPUT ;
    USE SIGNAL ;
    PORT
      LAYER Metal4 ;
        RECT 172.660000 0.000000 172.740000 0.250000 ;
    END
  END Q[18]
  PIN Q[17]
    DIRECTION OUTPUT ;
    USE SIGNAL ;
    PORT
      LAYER Metal6 ;
        RECT 170.460000 0.000000 170.540000 0.250000 ;
    END
  END Q[17]
  PIN Q[16]
    DIRECTION OUTPUT ;
    USE SIGNAL ;
    PORT
      LAYER Metal4 ;
        RECT 170.260000 0.000000 170.340000 0.250000 ;
    END
  END Q[16]
  PIN Q[15]
    DIRECTION OUTPUT ;
    USE SIGNAL ;
    PORT
      LAYER Metal6 ;
        RECT 168.060000 0.000000 168.140000 0.250000 ;
    END
  END Q[15]
  PIN Q[14]
    DIRECTION OUTPUT ;
    USE SIGNAL ;
    PORT
      LAYER Metal4 ;
        RECT 167.860000 0.000000 167.940000 0.250000 ;
    END
  END Q[14]
  PIN Q[13]
    DIRECTION OUTPUT ;
    USE SIGNAL ;
    PORT
      LAYER Metal6 ;
        RECT 165.660000 0.000000 165.740000 0.250000 ;
    END
  END Q[13]
  PIN Q[12]
    DIRECTION OUTPUT ;
    USE SIGNAL ;
    PORT
      LAYER Metal4 ;
        RECT 165.460000 0.000000 165.540000 0.250000 ;
    END
  END Q[12]
  PIN Q[11]
    DIRECTION OUTPUT ;
    USE SIGNAL ;
    PORT
      LAYER Metal6 ;
        RECT 163.260000 0.000000 163.340000 0.250000 ;
    END
  END Q[11]
  PIN Q[10]
    DIRECTION OUTPUT ;
    USE SIGNAL ;
    PORT
      LAYER Metal4 ;
        RECT 163.060000 0.000000 163.140000 0.250000 ;
    END
  END Q[10]
  PIN Q[9]
    DIRECTION OUTPUT ;
    USE SIGNAL ;
    PORT
      LAYER Metal6 ;
        RECT 160.860000 0.000000 160.940000 0.250000 ;
    END
  END Q[9]
  PIN Q[8]
    DIRECTION OUTPUT ;
    USE SIGNAL ;
    PORT
      LAYER Metal4 ;
        RECT 160.660000 0.000000 160.740000 0.250000 ;
    END
  END Q[8]
  PIN Q[7]
    DIRECTION OUTPUT ;
    USE SIGNAL ;
    PORT
      LAYER Metal6 ;
        RECT 158.460000 0.000000 158.540000 0.250000 ;
    END
  END Q[7]
  PIN Q[6]
    DIRECTION OUTPUT ;
    USE SIGNAL ;
    PORT
      LAYER Metal4 ;
        RECT 158.260000 0.000000 158.340000 0.250000 ;
    END
  END Q[6]
  PIN Q[5]
    DIRECTION OUTPUT ;
    USE SIGNAL ;
    PORT
      LAYER Metal6 ;
        RECT 156.060000 0.000000 156.140000 0.250000 ;
    END
  END Q[5]
  PIN Q[4]
    DIRECTION OUTPUT ;
    USE SIGNAL ;
    PORT
      LAYER Metal4 ;
        RECT 155.860000 0.000000 155.940000 0.250000 ;
    END
  END Q[4]
  PIN Q[3]
    DIRECTION OUTPUT ;
    USE SIGNAL ;
    PORT
      LAYER Metal6 ;
        RECT 153.660000 0.000000 153.740000 0.250000 ;
    END
  END Q[3]
  PIN Q[2]
    DIRECTION OUTPUT ;
    USE SIGNAL ;
    PORT
      LAYER Metal4 ;
        RECT 153.460000 0.000000 153.540000 0.250000 ;
    END
  END Q[2]
  PIN Q[1]
    DIRECTION OUTPUT ;
    USE SIGNAL ;
    PORT
      LAYER Metal6 ;
        RECT 151.260000 0.000000 151.340000 0.250000 ;
    END
  END Q[1]
  PIN Q[0]
    DIRECTION OUTPUT ;
    USE SIGNAL ;
    PORT
      LAYER Metal4 ;
        RECT 151.060000 0.000000 151.140000 0.250000 ;
    END
  END Q[0]
  PIN OBSV_CTL
    DIRECTION OUTPUT ;
    USE SIGNAL ;
    PORT
      LAYER Metal4 ;
        RECT 148.660000 0.000000 148.740000 0.250000 ;
    END
  END OBSV_CTL
  PIN VDD
    DIRECTION INPUT ;
    USE POWER ;
  END VDD
  PIN VSS
    DIRECTION INPUT ;
    USE GROUND ;
  END VSS
  OBS
    LAYER Metal1 ;
      RECT 0.000000 0.000000 345.600000 345.600000 ;
    LAYER Metal2 ;
      RECT 0.000000 0.000000 345.600000 345.600000 ;
    LAYER Metal3 ;
      RECT 0.000000 0.000000 345.600000 345.600000 ;
    LAYER Metal4 ;
      RECT 0.000000 0.330000 345.600000 345.600000 ;
      RECT 295.210000 0.000000 345.600000 0.330000 ;
      RECT 292.810000 0.000000 294.990000 0.330000 ;
      RECT 290.410000 0.000000 292.590000 0.330000 ;
      RECT 288.010000 0.000000 290.190000 0.330000 ;
      RECT 285.610000 0.000000 287.790000 0.330000 ;
      RECT 283.210000 0.000000 285.390000 0.330000 ;
      RECT 280.810000 0.000000 282.990000 0.330000 ;
      RECT 278.410000 0.000000 280.590000 0.330000 ;
      RECT 276.010000 0.000000 278.190000 0.330000 ;
      RECT 273.610000 0.000000 275.790000 0.330000 ;
      RECT 271.210000 0.000000 273.390000 0.330000 ;
      RECT 268.810000 0.000000 270.990000 0.330000 ;
      RECT 266.410000 0.000000 268.590000 0.330000 ;
      RECT 264.010000 0.000000 266.190000 0.330000 ;
      RECT 261.610000 0.000000 263.790000 0.330000 ;
      RECT 259.210000 0.000000 261.390000 0.330000 ;
      RECT 256.810000 0.000000 258.990000 0.330000 ;
      RECT 254.410000 0.000000 256.590000 0.330000 ;
      RECT 252.010000 0.000000 254.190000 0.330000 ;
      RECT 249.610000 0.000000 251.790000 0.330000 ;
      RECT 247.210000 0.000000 249.390000 0.330000 ;
      RECT 244.810000 0.000000 246.990000 0.330000 ;
      RECT 242.410000 0.000000 244.590000 0.330000 ;
      RECT 240.010000 0.000000 242.190000 0.330000 ;
      RECT 237.610000 0.000000 239.790000 0.330000 ;
      RECT 235.210000 0.000000 237.390000 0.330000 ;
      RECT 232.810000 0.000000 234.990000 0.330000 ;
      RECT 230.410000 0.000000 232.590000 0.330000 ;
      RECT 228.010000 0.000000 230.190000 0.330000 ;
      RECT 225.610000 0.000000 227.790000 0.330000 ;
      RECT 223.210000 0.000000 225.390000 0.330000 ;
      RECT 220.810000 0.000000 222.990000 0.330000 ;
      RECT 218.410000 0.000000 220.590000 0.330000 ;
      RECT 216.010000 0.000000 218.190000 0.330000 ;
      RECT 213.610000 0.000000 215.790000 0.330000 ;
      RECT 211.210000 0.000000 213.390000 0.330000 ;
      RECT 208.810000 0.000000 210.990000 0.330000 ;
      RECT 206.410000 0.000000 208.590000 0.330000 ;
      RECT 204.010000 0.000000 206.190000 0.330000 ;
      RECT 201.610000 0.000000 203.790000 0.330000 ;
      RECT 199.210000 0.000000 201.390000 0.330000 ;
      RECT 196.810000 0.000000 198.990000 0.330000 ;
      RECT 194.410000 0.000000 196.590000 0.330000 ;
      RECT 192.010000 0.000000 194.190000 0.330000 ;
      RECT 189.610000 0.000000 191.790000 0.330000 ;
      RECT 187.210000 0.000000 189.390000 0.330000 ;
      RECT 184.810000 0.000000 186.990000 0.330000 ;
      RECT 182.410000 0.000000 184.590000 0.330000 ;
      RECT 180.010000 0.000000 182.190000 0.330000 ;
      RECT 177.610000 0.000000 179.790000 0.330000 ;
      RECT 175.210000 0.000000 177.390000 0.330000 ;
      RECT 172.810000 0.000000 174.990000 0.330000 ;
      RECT 170.410000 0.000000 172.590000 0.330000 ;
      RECT 168.010000 0.000000 170.190000 0.330000 ;
      RECT 165.610000 0.000000 167.790000 0.330000 ;
      RECT 163.210000 0.000000 165.390000 0.330000 ;
      RECT 160.810000 0.000000 162.990000 0.330000 ;
      RECT 158.410000 0.000000 160.590000 0.330000 ;
      RECT 156.010000 0.000000 158.190000 0.330000 ;
      RECT 153.610000 0.000000 155.790000 0.330000 ;
      RECT 151.210000 0.000000 153.390000 0.330000 ;
      RECT 148.810000 0.000000 150.990000 0.330000 ;
      RECT 146.410000 0.000000 148.590000 0.330000 ;
      RECT 144.010000 0.000000 146.190000 0.330000 ;
      RECT 141.610000 0.000000 143.790000 0.330000 ;
      RECT 139.210000 0.000000 141.390000 0.330000 ;
      RECT 136.810000 0.000000 138.990000 0.330000 ;
      RECT 134.410000 0.000000 136.590000 0.330000 ;
      RECT 132.010000 0.000000 134.190000 0.330000 ;
      RECT 129.610000 0.000000 131.790000 0.330000 ;
      RECT 127.210000 0.000000 129.390000 0.330000 ;
      RECT 124.810000 0.000000 126.990000 0.330000 ;
      RECT 122.410000 0.000000 124.590000 0.330000 ;
      RECT 120.010000 0.000000 122.190000 0.330000 ;
      RECT 117.610000 0.000000 119.790000 0.330000 ;
      RECT 115.210000 0.000000 117.390000 0.330000 ;
      RECT 112.810000 0.000000 114.990000 0.330000 ;
      RECT 110.410000 0.000000 112.590000 0.330000 ;
      RECT 108.010000 0.000000 110.190000 0.330000 ;
      RECT 105.610000 0.000000 107.790000 0.330000 ;
      RECT 103.210000 0.000000 105.390000 0.330000 ;
      RECT 100.810000 0.000000 102.990000 0.330000 ;
      RECT 98.410000 0.000000 100.590000 0.330000 ;
      RECT 96.010000 0.000000 98.190000 0.330000 ;
      RECT 93.610000 0.000000 95.790000 0.330000 ;
      RECT 91.210000 0.000000 93.390000 0.330000 ;
      RECT 88.810000 0.000000 90.990000 0.330000 ;
      RECT 86.410000 0.000000 88.590000 0.330000 ;
      RECT 84.010000 0.000000 86.190000 0.330000 ;
      RECT 81.610000 0.000000 83.790000 0.330000 ;
      RECT 79.210000 0.000000 81.390000 0.330000 ;
      RECT 76.810000 0.000000 78.990000 0.330000 ;
      RECT 74.410000 0.000000 76.590000 0.330000 ;
      RECT 72.010000 0.000000 74.190000 0.330000 ;
      RECT 69.610000 0.000000 71.790000 0.330000 ;
      RECT 67.210000 0.000000 69.390000 0.330000 ;
      RECT 64.810000 0.000000 66.990000 0.330000 ;
      RECT 62.410000 0.000000 64.590000 0.330000 ;
      RECT 60.010000 0.000000 62.190000 0.330000 ;
      RECT 57.610000 0.000000 59.790000 0.330000 ;
      RECT 55.210000 0.000000 57.390000 0.330000 ;
      RECT 52.810000 0.000000 54.990000 0.330000 ;
      RECT 50.410000 0.000000 52.590000 0.330000 ;
      RECT 0.000000 0.000000 50.190000 0.330000 ;
    LAYER Metal5 ;
      RECT 0.000000 0.000000 345.600000 345.600000 ;
    LAYER Metal6 ;
      RECT 0.000000 0.330000 345.600000 345.600000 ;
      RECT 295.410000 0.000000 345.600000 0.330000 ;
      RECT 293.010000 0.000000 295.190000 0.330000 ;
      RECT 290.610000 0.000000 292.790000 0.330000 ;
      RECT 288.210000 0.000000 290.390000 0.330000 ;
      RECT 285.810000 0.000000 287.990000 0.330000 ;
      RECT 283.410000 0.000000 285.590000 0.330000 ;
      RECT 281.010000 0.000000 283.190000 0.330000 ;
      RECT 278.610000 0.000000 280.790000 0.330000 ;
      RECT 276.210000 0.000000 278.390000 0.330000 ;
      RECT 273.810000 0.000000 275.990000 0.330000 ;
      RECT 271.410000 0.000000 273.590000 0.330000 ;
      RECT 269.010000 0.000000 271.190000 0.330000 ;
      RECT 266.610000 0.000000 268.790000 0.330000 ;
      RECT 264.210000 0.000000 266.390000 0.330000 ;
      RECT 261.810000 0.000000 263.990000 0.330000 ;
      RECT 259.410000 0.000000 261.590000 0.330000 ;
      RECT 257.010000 0.000000 259.190000 0.330000 ;
      RECT 254.610000 0.000000 256.790000 0.330000 ;
      RECT 252.210000 0.000000 254.390000 0.330000 ;
      RECT 249.810000 0.000000 251.990000 0.330000 ;
      RECT 247.410000 0.000000 249.590000 0.330000 ;
      RECT 245.010000 0.000000 247.190000 0.330000 ;
      RECT 242.610000 0.000000 244.790000 0.330000 ;
      RECT 240.210000 0.000000 242.390000 0.330000 ;
      RECT 237.810000 0.000000 239.990000 0.330000 ;
      RECT 235.410000 0.000000 237.590000 0.330000 ;
      RECT 233.010000 0.000000 235.190000 0.330000 ;
      RECT 230.610000 0.000000 232.790000 0.330000 ;
      RECT 228.210000 0.000000 230.390000 0.330000 ;
      RECT 225.810000 0.000000 227.990000 0.330000 ;
      RECT 223.410000 0.000000 225.590000 0.330000 ;
      RECT 221.010000 0.000000 223.190000 0.330000 ;
      RECT 218.610000 0.000000 220.790000 0.330000 ;
      RECT 216.210000 0.000000 218.390000 0.330000 ;
      RECT 213.810000 0.000000 215.990000 0.330000 ;
      RECT 211.410000 0.000000 213.590000 0.330000 ;
      RECT 209.010000 0.000000 211.190000 0.330000 ;
      RECT 206.610000 0.000000 208.790000 0.330000 ;
      RECT 204.210000 0.000000 206.390000 0.330000 ;
      RECT 201.810000 0.000000 203.990000 0.330000 ;
      RECT 199.410000 0.000000 201.590000 0.330000 ;
      RECT 197.010000 0.000000 199.190000 0.330000 ;
      RECT 194.610000 0.000000 196.790000 0.330000 ;
      RECT 192.210000 0.000000 194.390000 0.330000 ;
      RECT 189.810000 0.000000 191.990000 0.330000 ;
      RECT 187.410000 0.000000 189.590000 0.330000 ;
      RECT 185.010000 0.000000 187.190000 0.330000 ;
      RECT 182.610000 0.000000 184.790000 0.330000 ;
      RECT 180.210000 0.000000 182.390000 0.330000 ;
      RECT 177.810000 0.000000 179.990000 0.330000 ;
      RECT 175.410000 0.000000 177.590000 0.330000 ;
      RECT 173.010000 0.000000 175.190000 0.330000 ;
      RECT 170.610000 0.000000 172.790000 0.330000 ;
      RECT 168.210000 0.000000 170.390000 0.330000 ;
      RECT 165.810000 0.000000 167.990000 0.330000 ;
      RECT 163.410000 0.000000 165.590000 0.330000 ;
      RECT 161.010000 0.000000 163.190000 0.330000 ;
      RECT 158.610000 0.000000 160.790000 0.330000 ;
      RECT 156.210000 0.000000 158.390000 0.330000 ;
      RECT 153.810000 0.000000 155.990000 0.330000 ;
      RECT 151.410000 0.000000 153.590000 0.330000 ;
      RECT 149.010000 0.000000 151.190000 0.330000 ;
      RECT 146.610000 0.000000 148.790000 0.330000 ;
      RECT 144.210000 0.000000 146.390000 0.330000 ;
      RECT 141.810000 0.000000 143.990000 0.330000 ;
      RECT 139.410000 0.000000 141.590000 0.330000 ;
      RECT 137.010000 0.000000 139.190000 0.330000 ;
      RECT 134.610000 0.000000 136.790000 0.330000 ;
      RECT 132.210000 0.000000 134.390000 0.330000 ;
      RECT 129.810000 0.000000 131.990000 0.330000 ;
      RECT 127.410000 0.000000 129.590000 0.330000 ;
      RECT 125.010000 0.000000 127.190000 0.330000 ;
      RECT 122.610000 0.000000 124.790000 0.330000 ;
      RECT 120.210000 0.000000 122.390000 0.330000 ;
      RECT 117.810000 0.000000 119.990000 0.330000 ;
      RECT 115.410000 0.000000 117.590000 0.330000 ;
      RECT 113.010000 0.000000 115.190000 0.330000 ;
      RECT 110.610000 0.000000 112.790000 0.330000 ;
      RECT 108.210000 0.000000 110.390000 0.330000 ;
      RECT 105.810000 0.000000 107.990000 0.330000 ;
      RECT 103.410000 0.000000 105.590000 0.330000 ;
      RECT 101.010000 0.000000 103.190000 0.330000 ;
      RECT 98.610000 0.000000 100.790000 0.330000 ;
      RECT 96.210000 0.000000 98.390000 0.330000 ;
      RECT 93.810000 0.000000 95.990000 0.330000 ;
      RECT 91.410000 0.000000 93.590000 0.330000 ;
      RECT 89.010000 0.000000 91.190000 0.330000 ;
      RECT 86.610000 0.000000 88.790000 0.330000 ;
      RECT 84.210000 0.000000 86.390000 0.330000 ;
      RECT 81.810000 0.000000 83.990000 0.330000 ;
      RECT 79.410000 0.000000 81.590000 0.330000 ;
      RECT 77.010000 0.000000 79.190000 0.330000 ;
      RECT 74.610000 0.000000 76.790000 0.330000 ;
      RECT 72.210000 0.000000 74.390000 0.330000 ;
      RECT 69.810000 0.000000 71.990000 0.330000 ;
      RECT 67.410000 0.000000 69.590000 0.330000 ;
      RECT 65.010000 0.000000 67.190000 0.330000 ;
      RECT 62.610000 0.000000 64.790000 0.330000 ;
      RECT 60.210000 0.000000 62.390000 0.330000 ;
      RECT 57.810000 0.000000 59.990000 0.330000 ;
      RECT 55.410000 0.000000 57.590000 0.330000 ;
      RECT 53.010000 0.000000 55.190000 0.330000 ;
      RECT 50.610000 0.000000 52.790000 0.330000 ;
      RECT 0.000000 0.000000 50.390000 0.330000 ;
    LAYER Metal7 ;
      RECT 0.000000 0.000000 345.600000 345.600000 ;
    LAYER Metal8 ;
      RECT 0.000000 0.000000 345.600000 345.600000 ;
    LAYER Metal9 ;
      RECT 0.000000 0.000000 345.600000 345.600000 ;
    LAYER Metal10 ;
      RECT 0.000000 0.000000 345.600000 345.600000 ;
  END
END IN22FDX_S1DU_BFUG_W00256B032M04C128

END LIBRARY
